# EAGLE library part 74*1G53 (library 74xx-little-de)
SINGLE-POLE DOUBLE-THROW (SPDT) ANALOG SWITCH 2:1 ANALOG MULTIPLEXER/DEMULTIPLEXER Source: http://focus.ti.com/lit/ds/symlink/sn74lvc2g53.pdf

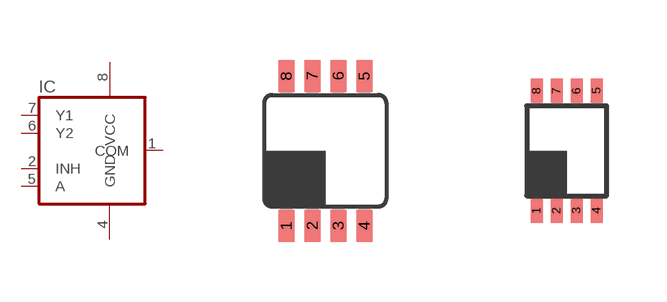
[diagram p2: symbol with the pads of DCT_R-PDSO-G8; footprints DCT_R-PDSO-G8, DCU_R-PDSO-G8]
Designator prefix IC

## 741G53DCT  [DCT_R-PDSO-G8]
1  COM
2  INH  in
4  GND
5  A  in
6  Y2
7  Y1
8  VCC

## 741G53DCU  [DCU_R-PDSO-G8]
1  COM
2  INH  in
5  A  in
6  Y2
7  Y1

## 741G53YEA  [YEA_R-XBGA-N8]
A1  COM
B1  INH  in
B2  Y1
C2  Y2
D2  A  in

## 741G53YEP  [YEP_R-XBGA-N8]
Pads as for YEA_R-XBGA-N8

## 741G53YZA  [YZA_R-XBGA-N8]
Pads as for YEA_R-XBGA-N8

## Footprint DCT_R-PDSO-G8 (pad centres in mm)
DCT (R-PDSO-G8) PLSTIG SMALL-OUTLINE PACKAGE Source: http://focus.ti.com/lit/ds/symlink/sn74lvc2g53.pdf
smd 0.4 x 0.8: 1 -0.975,-1.875; 2 -0.325,-1.875; 3 0.325,-1.875; 4 0.975,-1.875; 5 0.975,1.875; 6 0.325,1.875; 7 -0.325,1.875; 8 -0.975,1.875

## Footprint DCU_R-PDSO-G8 (pad centres in mm)
DCU (R-PDSO-G8) PLASTIC SMALL-OUTLINE PACKAGE (DIE DOWN) Source: http://focus.ti.com/lit/ds/symlink/sn74lvc2g53.pdf
smd 0.3 x 0.6: 1 -0.75,-1.5; 2 -0.25,-1.5; 3 0.25,-1.5; 4 0.75,-1.5; 5 0.75,1.5; 6 0.25,1.5; 7 -0.25,1.5; 8 -0.75,1.5

## Footprint YEA_R-XBGA-N8 (pad centres in mm)
YEA (R-XBGA-N8) DIE-SIZE BALL GRID ARRAY Source: http://focus.ti.com/lit/ds/symlink/sn74lvc2g53.pdf
smd 0.25 x 0.25: A1 -0.75,-0.25; A2 -0.75,0.25; B1 -0.25,-0.25; B2 -0.25,0.25; C1 0.25,-0.25; C2 0.25,0.25; D1 0.75,-0.25; D2 0.75,0.25

## Footprint YEP_R-XBGA-N8 (pad centres in mm)
YEP (R-XBGA-N8) DIE-SIZE BALL GRID ARRAY Source: http://focus.ti.com/lit/ds/symlink/sn74lvc2g53.pdf
smd 0.3 x 0.3: A1 -0.75,-0.25; A2 -0.75,0.25; B1 -0.25,-0.25; B2 -0.25,0.25; C1 0.25,-0.25; C2 0.25,0.25; D1 0.75,-0.25; D2 0.75,0.25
